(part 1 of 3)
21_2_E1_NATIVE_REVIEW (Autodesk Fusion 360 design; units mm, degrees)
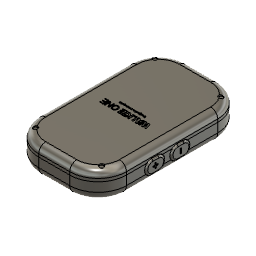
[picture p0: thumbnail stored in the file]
description: Open CASCADE Model
part number: ASSEMBLY
description: Part Number
part number: SOLID
part number: vol_minus_pad_silicone
part number: pcb_clamp_pad_silicone_1_0to0_8_3
part number: play_action_cap_cream
part number: status_lens_clear_diffusing
base_feature "Base Feature1"
base_feature "Base Feature1"
base_feature "Base Feature1"
base_feature "Base Feature1"
base_feature "Base Feature1"
base_feature "Base Feature1"
base_feature "Base Feature1"
base_feature "Base Feature1"
base_feature "Base Feature1"
base_feature "Base Feature1"
base_feature "Base Feature1"
base_feature "Base Feature1"
base_feature "Base Feature1"
base_feature "Base Feature1"
base_feature "Base Feature1"
base_feature "Base Feature1"
base_feature "Base Feature1"
base_feature "Base Feature1"
base_feature "Base Feature1"
base_feature "Base Feature1"
base_feature "Base Feature1"
base_feature "Base Feature1"
base_feature "Base Feature1"
base_feature "Base Feature1"
base_feature "Base Feature1"
base_feature "Base Feature1"
base_feature "Base Feature1"
base_feature "Base Feature1"
base_feature "Base Feature1"
base_feature "Base Feature1"
base_feature "Base Feature1"
base_feature "Base Feature1"
base_feature "Base Feature1"
base_feature "Base Feature1"
base_feature "Base Feature1"
base_feature "Base Feature1"
base_feature "Base Feature1"
base_feature "Base Feature1"
base_feature "Base Feature1"
base_feature "Base Feature1"
base_feature "Base Feature1"
base_feature "Base Feature1"
base_feature "Base Feature1"
base_feature "Base Feature1"
base_feature "Base Feature1"
base_feature "Base Feature1"
base_feature "Base Feature1"
base_feature "Base Feature1"
base_feature "Base Feature1"
base_feature "Base Feature1"
base_feature "Base Feature1"
base_feature "Base Feature1"
base_feature "Base Feature1"
base_feature "Base Feature1"
base_feature "Base Feature1"
base_feature "Base Feature1"
base_feature "Base Feature1"
base_feature "Base Feature1"
base_feature "Base Feature1"
base_feature "Base Feature1"
base_feature "Base Feature1"
base_feature "Base Feature1"
base_feature "Base Feature1"
base_feature "Base Feature1"
base_feature "Base Feature1"
base_feature "Base Feature1"
base_feature "Base Feature1"
base_feature "Base Feature1"
base_feature "Base Feature1"
base_feature "Base Feature1"
base_feature "Base Feature1"
base_feature "Base Feature1"
base_feature "Base Feature1"
base_feature "Base Feature1"
base_feature "Base Feature1"
base_feature "Base Feature1"
base_feature "Base Feature1"
base_feature "Base Feature1"
base_feature "Base Feature1"
base_feature "Base Feature1"
base_feature "Base Feature1"
base_feature "Base Feature1"
base_feature "Base Feature1"
base_feature "Base Feature1"
base_feature "Base Feature1"
base_feature "Base Feature1"
base_feature "Base Feature1"
base_feature "Base Feature1"
base_feature "Base Feature1"
base_feature "Base Feature1"
base_feature "Base Feature1"
base_feature "Base Feature1"
base_feature "Base Feature1"
base_feature "Base Feature1"
base_feature "Base Feature1"
base_feature "Base Feature1"
base_feature "Base Feature1"
base_feature "Base Feature1"
base_feature "Base Feature1"
base_feature "Base Feature1"
base_feature "Base Feature1"
base_feature "Base Feature1"
base_feature "Base Feature1"
base_feature "Base Feature1"
base_feature "Base Feature1"
base_feature "Base Feature1"
base_feature "Base Feature1"
base_feature "Base Feature1"
base_feature "Base Feature1"
base_feature "Base Feature1"
base_feature "Base Feature1"
base_feature "Base Feature1"
base_feature "Base Feature1"
base_feature "Base Feature1"
base_feature "Base Feature1"
base_feature "Base Feature1"
base_feature "Base Feature1"
base_feature "Base Feature1"
base_feature "Base Feature1"
base_feature "Base Feature1"
base_feature "Base Feature1"
base_feature "Base Feature1"
base_feature "Base Feature1"
base_feature "Base Feature1"
base_feature "Base Feature1"
base_feature "Base Feature1"
base_feature "Base Feature1"
base_feature "Base Feature1"
base_feature "Base Feature1"
base_feature "Base Feature1"
base_feature "Base Feature1"
base_feature "Base Feature1"
base_feature "Base Feature1"
base_feature "Base Feature1"
base_feature "Base Feature1"
base_feature "Base Feature1"
base_feature "Base Feature1"
base_feature "Base Feature1"
base_feature "Base Feature1"
base_feature "Base Feature1"
base_feature "Base Feature1"
base_feature "Base Feature1"
base_feature "Base Feature1"
base_feature "Base Feature1"
base_feature "Base Feature1"
base_feature "Base Feature1"
base_feature "Base Feature1"
base_feature "Base Feature1"
base_feature "Base Feature1"
base_feature "Base Feature1"
base_feature "Base Feature1"
base_feature "Base Feature1"
base_feature "Base Feature1"
base_feature "Base Feature1"
base_feature "Base Feature1"
base_feature "Base Feature1"
base_feature "Base Feature1"
base_feature "Base Feature1"
base_feature "Base Feature1"
base_feature "Base Feature1"
base_feature "Base Feature1"
base_feature "Base Feature1"
base_feature "Base Feature1"
base_feature "Base Feature1"
base_feature "Base Feature1"
base_feature "Base Feature1"
base_feature "Base Feature1"
base_feature "Base Feature1"
base_feature "Base Feature1"
base_feature "Base Feature1"
base_feature "Base Feature1"
base_feature "Base Feature1"
base_feature "Base Feature1"
base_feature "Base Feature1"
base_feature "Base Feature1"
base_feature "Base Feature1"
base_feature "Base Feature1"
base_feature "Base Feature1"
base_feature "Base Feature1"
base_feature "Base Feature1"
base_feature "Base Feature1"
base_feature "Base Feature1"
base_feature "Base Feature1"
base_feature "Base Feature1"
base_feature "Base Feature1"
base_feature "Base Feature1"
base_feature "Base Feature1"
base_feature "Base Feature1"
base_feature "Base Feature1"
base_feature "Base Feature1"
base_feature "Base Feature1"
base_feature "Base Feature1"
base_feature "Base Feature1"
base_feature "Base Feature1"
base_feature "Base Feature1"
base_feature "Base Feature1"
base_feature "Base Feature1"
base_feature "Base Feature1"
base_feature "Base Feature1"
base_feature "Base Feature1"
base_feature "Base Feature1"
base_feature "Base Feature1"
base_feature "Base Feature1"
base_feature "Base Feature1"
base_feature "Base Feature1"
base_feature "Base Feature1"
base_feature "Base Feature1"
base_feature "Base Feature1"
base_feature "Base Feature1"
base_feature "Base Feature1"
base_feature "Base Feature1"
base_feature "Base Feature1"
base_feature "Base Feature1"
base_feature "Base Feature1"
base_feature "Base Feature1"
base_feature "Base Feature1"
base_feature "Base Feature1"
base_feature "Base Feature1"
base_feature "Base Feature1"
base_feature "Base Feature1"
base_feature "Base Feature1"
base_feature "Base Feature1"
base_feature "Base Feature1"
base_feature "Base Feature1"
base_feature "Base Feature1"
base_feature "Base Feature1"
base_feature "Base Feature1"
base_feature "Base Feature1"
base_feature "Base Feature1"
base_feature "Base Feature1"
base_feature "Base Feature1"
base_feature "Base Feature1"
base_feature "Base Feature1"
base_feature "Base Feature1"
base_feature "Base Feature1"
base_feature "Base Feature1"
base_feature "Base Feature1"
base_feature "Base Feature1"
base_feature "Base Feature1"
base_feature "Base Feature1"
base_feature "Base Feature1"
base_feature "Base Feature1"
base_feature "Base Feature1"
base_feature "Base Feature1"
base_feature "Base Feature1"
base_feature "Base Feature1"
base_feature "Base Feature1"
base_feature "Base Feature1"
base_feature "Base Feature1"
base_feature "Base Feature1"
base_feature "Base Feature1"
base_feature "Base Feature1"
base_feature "Base Feature1"
base_feature "Base Feature1"
base_feature "Base Feature1"
base_feature "Base Feature1"
base_feature "Base Feature1"
base_feature "Base Feature1"
base_feature "Base Feature1"
base_feature "Base Feature1"
base_feature "Base Feature1"
base_feature "Base Feature1"
base_feature "Base Feature1"
base_feature "Base Feature1"
base_feature "Base Feature1"
base_feature "Base Feature1"
base_feature "Base Feature1"
base_feature "Base Feature1"
base_feature "Base Feature1"
base_feature "Base Feature1"
base_feature "Base Feature1"
base_feature "Base Feature1"
base_feature "Base Feature1"
base_feature "Base Feature1"
base_feature "Base Feature1"
base_feature "Base Feature1"
base_feature "Base Feature1"
base_feature "Base Feature1"
base_feature "Base Feature1"
base_feature "Base Feature1"
base_feature "Base Feature1"
base_feature "Base Feature1"
base_feature "Base Feature1"
base_feature "Base Feature1"
base_feature "Base Feature1"
base_feature "Base Feature1"
base_feature "Base Feature1"
base_feature "Base Feature1"
base_feature "Base Feature1"
base_feature "Base Feature1"
base_feature "Base Feature1"
base_feature "Base Feature1"
base_feature "Base Feature1"
base_feature "Base Feature1"
base_feature "Base Feature1"
base_feature "Base Feature1"
base_feature "Base Feature1"
base_feature "Base Feature1"
base_feature "Base Feature1"
base_feature "Base Feature1"
base_feature "Base Feature1"
base_feature "Base Feature1"
base_feature "Base Feature1"
base_feature "Base Feature1"
base_feature "Base Feature1"
base_feature "Base Feature1"
base_feature "Base Feature1"
base_feature "Base Feature1"
base_feature "Base Feature1"
base_feature "Base Feature1"
base_feature "Base Feature1"
base_feature "Base Feature1"
base_feature "Base Feature1"
base_feature "Base Feature1"
base_feature "Base Feature1"
base_feature "Base Feature1"
base_feature "Base Feature1"
base_feature "Base Feature1"
base_feature "Base Feature1"
base_feature "Base Feature1"
base_feature "Base Feature1"
base_feature "Base Feature1"
base_feature "Base Feature1"
base_feature "Base Feature1"
base_feature "Base Feature1"
base_feature "Base Feature1"
base_feature "Base Feature1"
base_feature "Base Feature1"
base_feature "Base Feature1"
base_feature "Base Feature1"
base_feature "Base Feature1"
base_feature "Base Feature1"
base_feature "Base Feature1"
base_feature "Base Feature1"
base_feature "Base Feature1"
base_feature "Base Feature1"
base_feature "Base Feature1"
base_feature "Base Feature1"
base_feature "Base Feature1"
base_feature "Base Feature1"
base_feature "Base Feature1"
base_feature "Base Feature1"
base_feature "Base Feature1"
base_feature "Base Feature1"
base_feature "Base Feature1"
base_feature "Base Feature1"
base_feature "Base Feature1"
base_feature "Base Feature1"
base_feature "Base Feature1"
base_feature "Base Feature1"
base_feature "Base Feature1"
base_feature "Base Feature1"
base_feature "Base Feature1"
base_feature "Base Feature1"
base_feature "Base Feature1"
base_feature "Base Feature1"
base_feature "Base Feature1"
base_feature "Base Feature1"
base_feature "Base Feature1"
base_feature "Base Feature1"
base_feature "Base Feature1"
base_feature "Base Feature1"
base_feature "Base Feature1"
base_feature "Base Feature1"
base_feature "Base Feature1"
base_feature "Base Feature1"
base_feature "Base Feature1"
base_feature "Base Feature1"
base_feature "Base Feature1"
base_feature "Base Feature1"
base_feature "Base Feature1"
base_feature "Base Feature1"
base_feature "Base Feature1"
base_feature "Base Feature1"
base_feature "Base Feature1"
base_feature "Base Feature1"
base_feature "Base Feature1"
base_feature "Base Feature1"
base_feature "Base Feature1"
base_feature "Base Feature1"
base_feature "Base Feature1"
base_feature "Base Feature1"
base_feature "Base Feature1"
base_feature "Base Feature1"
base_feature "Base Feature1"
base_feature "Base Feature1"
base_feature "Base Feature1"
base_feature "Base Feature1"
base_feature "Base Feature1"
base_feature "Base Feature1"
base_feature "Base Feature1"
base_feature "Base Feature1"
base_feature "Base Feature1"
base_feature "Base Feature1"
base_feature "Base Feature1"
base_feature "Base Feature1"
base_feature "Base Feature1"
base_feature "Base Feature1"
base_feature "Base Feature1"
base_feature "Base Feature1"
base_feature "Base Feature1"
base_feature "Base Feature1"
base_feature "Base Feature1"
base_feature "Base Feature1"
base_feature "Base Feature1"
base_feature "Base Feature1"
base_feature "Base Feature1"
base_feature "Base Feature1"
base_feature "Base Feature1"
base_feature "Base Feature1"
base_feature "Base Feature1"
base_feature "Base Feature1"
base_feature "Base Feature1"
base_feature "Base Feature1"
base_feature "Base Feature1"
base_feature "Base Feature1"
base_feature "Base Feature1"
base_feature "Base Feature1"
base_feature "Base Feature1"
base_feature "Base Feature1"
base_feature "Base Feature1"
base_feature "Base Feature1"
base_feature "Base Feature1"
base_feature "Base Feature1"
base_feature "Base Feature1"
base_feature "Base Feature1"
base_feature "Base Feature1"
base_feature "Base Feature1"
base_feature "Base Feature1"
base_feature "Base Feature1"
base_feature "Base Feature1"
base_feature "Base Feature1"
base_feature "Base Feature1"
base_feature "Base Feature1"
base_feature "Base Feature1"
base_feature "Base Feature1"
base_feature "Base Feature1"
base_feature "Base Feature1"
base_feature "Base Feature1"
base_feature "Base Feature1"
base_feature "Base Feature1"
base_feature "Base Feature1"
base_feature "Base Feature1"
base_feature "Base Feature1"
base_feature "Base Feature1"
base_feature "Base Feature1"
base_feature "Base Feature1"
base_feature "Base Feature1"
base_feature "Base Feature1"
base_feature "Base Feature1"
base_feature "Base Feature1"
base_feature "Base Feature1"
base_feature "Base Feature1"
base_feature "Base Feature1"
base_feature "Base Feature1"
base_feature "Base Feature1"
base_feature "Base Feature1"
base_feature "Base Feature1"
base_feature "Base Feature1"
base_feature "Base Feature1"
base_feature "Base Feature1"
base_feature "Base Feature1"
base_feature "Base Feature1"
base_feature "Base Feature1"
base_feature "Base Feature1"
base_feature "Base Feature1"
base_feature "Base Feature1"
base_feature "Base Feature1"
base_feature "Base Feature1"
base_feature "Base Feature1"
base_feature "Base Feature1"
base_feature "Base Feature1"
base_feature "Base Feature1"
base_feature "Base Feature1"
base_feature "Base Feature1"
base_feature "Base Feature1"
base_feature "Base Feature1"
base_feature "Base Feature1"
base_feature "Base Feature1"
base_feature "Base Feature1"
base_feature "Base Feature1"
base_feature "Base Feature1"
base_feature "Base Feature1"
base_feature "Base Feature1"
base_feature "Base Feature1"
base_feature "Base Feature1"
base_feature "Base Feature1"
base_feature "Base Feature1"
base_feature "Base Feature1"
base_feature "Base Feature1"
base_feature "Base Feature1"
base_feature "Base Feature1"
base_feature "Base Feature1"
base_feature "Base Feature1"
base_feature "Base Feature1"
base_feature "Base Feature1"
base_feature "Base Feature1"
base_feature "Base Feature1"
base_feature "Base Feature1"
base_feature "Base Feature1"
base_feature "Base Feature1"
base_feature "Base Feature1"
base_feature "Base Feature1"
base_feature "Base Feature1"
base_feature "Base Feature1"
base_feature "Base Feature1"
base_feature "Base Feature1"
base_feature "Base Feature1"
base_feature "Base Feature1"
base_feature "Base Feature1"
base_feature "Base Feature1"
base_feature "Base Feature1"
base_feature "Base Feature1"
base_feature "Base Feature1"
base_feature "Base Feature1"
base_feature "Base Feature1"
base_feature "Base Feature1"
base_feature "Base Feature1"
base_feature "Base Feature1"
base_feature "Base Feature1"
base_feature "Base Feature1"
base_feature "Base Feature1"
base_feature "Base Feature1"
base_feature "Base Feature1"
base_feature "Base Feature1"
base_feature "Base Feature1"
base_feature "Base Feature1"
base_feature "Base Feature1"
base_feature "Base Feature1"
base_feature "Base Feature1"
base_feature "Base Feature1"
base_feature "Base Feature1"
base_feature "Base Feature1"
base_feature "Base Feature1"
base_feature "Base Feature1"
base_feature "Base Feature1"
base_feature "Base Feature1"
base_feature "Base Feature1"
base_feature "Base Feature1"
base_feature "Base Feature1"
base_feature "Base Feature1"
base_feature "Base Feature1"
base_feature "Base Feature1"
base_feature "Base Feature1"
base_feature "Base Feature1"
base_feature "Base Feature1"
base_feature "Base Feature1"
base_feature "Base Feature1"
base_feature "Base Feature1"
base_feature "Base Feature1"
base_feature "Base Feature1"
base_feature "Base Feature1"
base_feature "Base Feature1"
base_feature "Base Feature1"
base_feature "Base Feature1"
base_feature "Base Feature1"
base_feature "Base Feature1"
base_feature "Base Feature1"
base_feature "Base Feature1"
base_feature "Base Feature1"
base_feature "Base Feature1"
base_feature "Base Feature1"
base_feature "Base Feature1"
base_feature "Base Feature1"
base_feature "Base Feature1"
base_feature "Base Feature1"
base_feature "Base Feature1"
base_feature "Base Feature1"
base_feature "Base Feature1"
base_feature "Base Feature1"
base_feature "Base Feature1"
base_feature "Base Feature1"
base_feature "Base Feature1"
base_feature "Base Feature1"
base_feature "Base Feature1"
base_feature "Base Feature1"
base_feature "Base Feature1"
base_feature "Base Feature1"
base_feature "Base Feature1"
base_feature "Base Feature1"
base_feature "Base Feature1"
base_feature "Base Feature1"
base_feature "Base Feature1"
base_feature "Base Feature1"
base_feature "Base Feature1"
base_feature "Base Feature1"
base_feature "Base Feature1"
base_feature "Base Feature1"
base_feature "Base Feature1"
base_feature "Base Feature1"
base_feature "Base Feature1"
base_feature "Base Feature1"
base_feature "Base Feature1"
base_feature "Base Feature1"
base_feature "Base Feature1"
base_feature "Base Feature1"
base_feature "Base Feature1"
base_feature "Base Feature1"
base_feature "Base Feature1"
base_feature "Base Feature1"
base_feature "Base Feature1"
base_feature "Base Feature1"
base_feature "Base Feature1"
base_feature "Base Feature1"
base_feature "Base Feature1"
base_feature "Base Feature1"
base_feature "Base Feature1"
base_feature "Base Feature1"
base_feature "Base Feature1"
base_feature "Base Feature1"
base_feature "Base Feature1"
base_feature "Base Feature1"
base_feature "Base Feature1"
base_feature "Base Feature1"
base_feature "Base Feature1"
base_feature "Base Feature1"
base_feature "Base Feature1"
base_feature "Base Feature1"
base_feature "Base Feature1"
base_feature "Base Feature1"
base_feature "Base Feature1"
base_feature "Base Feature1"
base_feature "Base Feature1"
base_feature "Base Feature1"
base_feature "Base Feature1"
base_feature "Base Feature1"
base_feature "Base Feature1"
base_feature "Base Feature1"
base_feature "Base Feature1"
base_feature "Base Feature1"
base_feature "Base Feature1"
base_feature "Base Feature1"
base_feature "Base Feature1"
base_feature "Base Feature1"
base_feature "Base Feature1"
base_feature "Base Feature1"
base_feature "Base Feature1"
base_feature "Base Feature1"
base_feature "Base Feature1"
base_feature "Base Feature1"
base_feature "Base Feature1"
base_feature "Base Feature1"
base_feature "Base Feature1"
base_feature "Base Feature1"
base_feature "Base Feature1"
base_feature "Base Feature1"
base_feature "Base Feature1"
base_feature "Base Feature1"
base_feature "Base Feature1"
base_feature "Base Feature1"
base_feature "Base Feature1"
base_feature "Base Feature1"
base_feature "Base Feature1"
base_feature "Base Feature1"
base_feature "Base Feature1"
base_feature "Base Feature1"
base_feature "Base Feature1"
base_feature "Base Feature1"
base_feature "Base Feature1"
base_feature "Base Feature1"
base_feature "Base Feature1"
base_feature "Base Feature1"
base_feature "Base Feature1"
base_feature "Base Feature1"
base_feature "Base Feature1"
base_feature "Base Feature1"
base_feature "Base Feature1"
base_feature "Base Feature1"
base_feature "Base Feature1"
base_feature "Base Feature1"
base_feature "Base Feature1"
base_feature "Base Feature1"
base_feature "Base Feature1"
base_feature "Base Feature1"
base_feature "Base Feature1"
base_feature "Base Feature1"
base_feature "Base Feature1"
base_feature "Base Feature1"
base_feature "Base Feature1"
base_feature "Base Feature1"
base_feature "Base Feature1"
base_feature "Base Feature1"
base_feature "Base Feature1"
base_feature "Base Feature1"
base_feature "Base Feature1"
base_feature "Base Feature1"
base_feature "Base Feature1"
base_feature "Base Feature1"
base_feature "Base Feature1"
base_feature "Base Feature1"
base_feature "Base Feature1"
base_feature "Base Feature1"
base_feature "Base Feature1"
base_feature "Base Feature1"
base_feature "Base Feature1"
base_feature "Base Feature1"
base_feature "Base Feature1"
base_feature "Base Feature1"
base_feature "Base Feature1"
base_feature "Base Feature1"
base_feature "Base Feature1"
base_feature "Base Feature1"
base_feature "Base Feature1"
base_feature "Base Feature1"
base_feature "Base Feature1"
base_feature "Base Feature1"
base_feature "Base Feature1"
base_feature "Base Feature1"
base_feature "Base Feature1"
base_feature "Base Feature1"
base_feature "Base Feature1"
base_feature "Base Feature1"
base_feature "Base Feature1"
base_feature "Base Feature1"
base_feature "Base Feature1"
base_feature "Base Feature1"
base_feature "Base Feature1"
base_feature "Base Feature1"
base_feature "Base Feature1"
base_feature "Base Feature1"
base_feature "Base Feature1"
base_feature "Base Feature1"
base_feature "Base Feature1"
base_feature "Base Feature1"
base_feature "Base Feature1"
base_feature "Base Feature1"
base_feature "Base Feature1"
base_feature "Base Feature1"
base_feature "Base Feature1"
base_feature "Base Feature1"
base_feature "Base Feature1"
base_feature "Base Feature1"
base_feature "Base Feature1"
base_feature "Base Feature1"
base_feature "Base Feature1"
base_feature "Base Feature1"
base_feature "Base Feature1"
base_feature "Base Feature1"
base_feature "Base Feature1"
base_feature "Base Feature1"
base_feature "Base Feature1"
base_feature "Base Feature1"
base_feature "Base Feature1"
base_feature "Base Feature1"
base_feature "Base Feature1"
base_feature "Base Feature1"
base_feature "Base Feature1"
base_feature "Base Feature1"
base_feature "Base Feature1"
base_feature "Base Feature1"
base_feature "Base Feature1"
base_feature "Base Feature1"
base_feature "Base Feature1"
base_feature "Base Feature1"
base_feature "Base Feature1"
base_feature "Base Feature1"
base_feature "Base Feature1"
base_feature "Base Feature1"
base_feature "Base Feature1"
base_feature "Base Feature1"
base_feature "Base Feature1"
base_feature "Base Feature1"
base_feature "Base Feature1"
base_feature "Base Feature1"
base_feature "Base Feature1"
base_feature "Base Feature1"
base_feature "Base Feature1"
base_feature "Base Feature1"
base_feature "Base Feature1"
base_feature "Base Feature1"
base_feature "Base Feature1"
base_feature "Base Feature1"
base_feature "Base Feature1"
base_feature "Base Feature1"
base_feature "Base Feature1"
base_feature "Base Feature1"
base_feature "Base Feature1"
base_feature "Base Feature1"
base_feature "Base Feature1"
base_feature "Base Feature1"
base_feature "Base Feature1"
base_feature "Base Feature1"
base_feature "Base Feature1"
base_feature "Base Feature1"
base_feature "Base Feature1"
base_feature "Base Feature1"
base_feature "Base Feature1"
base_feature "Base Feature1"
base_feature "Base Feature1"
base_feature "Base Feature1"
base_feature "Base Feature1"
base_feature "Base Feature1"
base_feature "Base Feature1"
base_feature "Base Feature1"
base_feature "Base Feature1"
base_feature "Base Feature1"
base_feature "Base Feature1"
base_feature "Base Feature1"
base_feature "Base Feature1"
base_feature "Base Feature1"
base_feature "Base Feature1"
base_feature "Base Feature1"
base_feature "Base Feature1"
base_feature "Base Feature1"
base_feature "Base Feature1"
base_feature "Base Feature1"
base_feature "Base Feature1"
base_feature "Base Feature1"
base_feature "Base Feature1"
base_feature "Base Feature1"
base_feature "Base Feature1"
base_feature "Base Feature1"
base_feature "Base Feature1"
base_feature "Base Feature1"
base_feature "Base Feature1"
base_feature "Base Feature1"
base_feature "Base Feature1"
base_feature "Base Feature1"
base_feature "Base Feature1"
base_feature "Base Feature1"
base_feature "Base Feature1"
base_feature "Base Feature1"
base_feature "Base Feature1"
base_feature "Base Feature1"
base_feature "Base Feature1"
base_feature "Base Feature1"
base_feature "Base Feature1"
base_feature "Base Feature1"
base_feature "Base Feature1"
base_feature "Base Feature1"
base_feature "Base Feature1"
base_feature "Base Feature1"
base_feature "Base Feature1"
base_feature "Base Feature1"
base_feature "Base Feature1"
base_feature "Base Feature1"
base_feature "Base Feature1"
base_feature "Base Feature1"
base_feature "Base Feature1"
base_feature "Base Feature1"
base_feature "Base Feature1"
base_feature "Base Feature1"
base_feature "Base Feature1"
base_feature "Base Feature1"
base_feature "Base Feature1"
base_feature "Base Feature1"
base_feature "Base Feature1"
base_feature "Base Feature1"
base_feature "Base Feature1"
base_feature "Base Feature1"
base_feature "Base Feature1"
base_feature "Base Feature1"
base_feature "Base Feature1"
base_feature "Base Feature1"
base_feature "Base Feature1"
base_feature "Base Feature1"
base_feature "Base Feature1"
base_feature "Base Feature1"
base_feature "Base Feature1"
base_feature "Base Feature1"
base_feature "Base Feature1"
base_feature "Base Feature1"
base_feature "Base Feature1"
base_feature "Base Feature1"
base_feature "Base Feature1"
base_feature "Base Feature1"
base_feature "Base Feature1"
base_feature "Base Feature1"
base_feature "Base Feature1"
base_feature "Base Feature1"
base_feature "Base Feature1"
base_feature "Base Feature1"
base_feature "Base Feature1"
base_feature "Base Feature1"
base_feature "Base Feature1"
base_feature "Base Feature1"
base_feature "Base Feature1"
base_feature "Base Feature1"
base_feature "Base Feature1"
base_feature "Base Feature1"
base_feature "Base Feature1"
base_feature "Base Feature1"
base_feature "Base Feature1"
base_feature "Base Feature1"
base_feature "Base Feature1"
base_feature "Base Feature1"
base_feature "Base Feature1"
base_feature "Base Feature1"
base_feature "Base Feature1"
base_feature "Base Feature1"
base_feature "Base Feature1"
base_feature "Base Feature1"
base_feature "Base Feature1"
base_feature "Base Feature1"
base_feature "Base Feature1"
base_feature "Base Feature1"
base_feature "Base Feature1"
base_feature "Base Feature1"
base_feature "Base Feature1"
base_feature "Base Feature1"
base_feature "Base Feature1"
base_feature "Base Feature1"
base_feature "Base Feature1"
base_feature "Base Feature1"
base_feature "Base Feature1"
base_feature "Base Feature1"
base_feature "Base Feature1"
base_feature "Base Feature1"
base_feature "Base Feature1"
base_feature "Base Feature1"
base_feature "Base Feature1"
base_feature "Base Feature1"
base_feature "Base Feature1"
base_feature "Base Feature1"
base_feature "Base Feature1"
base_feature "Base Feature1"
base_feature "Base Feature1"
base_feature "Base Feature1"
base_feature "Base Feature1"
base_feature "Base Feature1"
base_feature "Base Feature1"
base_feature "Base Feature1"
base_feature "Base Feature1"
base_feature "Base Feature1"
base_feature "Base Feature1"
base_feature "Base Feature1"
base_feature "Base Feature1"
base_feature "Base Feature1"
base_feature "Base Feature1"
base_feature "Base Feature1"
base_feature "Base Feature1"
base_feature "Base Feature1"
base_feature "Base Feature1"
base_feature "Base Feature1"
base_feature "Base Feature1"
base_feature "Base Feature1"
base_feature "Base Feature1"
base_feature "Base Feature1"
base_feature "Base Feature1"
base_feature "Base Feature1"
base_feature "Base Feature1"
base_feature "Base Feature1"
base_feature "Base Feature1"
base_feature "Base Feature1"
base_feature "Base Feature1"
base_feature "Base Feature1"
base_feature "Base Feature1"
base_feature "Base Feature1"
base_feature "Base Feature1"
base_feature "Base Feature1"
base_feature "Base Feature1"
base_feature "Base Feature1"
base_feature "Base Feature1"
base_feature "Base Feature1"
base_feature "Base Feature1"
base_feature "Base Feature1"
base_feature "Base Feature1"
base_feature "Base Feature1"
base_feature "Base Feature1"
base_feature "Base Feature1"
base_feature "Base Feature1"
base_feature "Base Feature1"
base_feature "Base Feature1"
base_feature "Base Feature1"
base_feature "Base Feature1"
base_feature "Base Feature1"
base_feature "Base Feature1"
base_feature "Base Feature1"
base_feature "Base Feature1"
base_feature "Base Feature1"
base_feature "Base Feature1"
base_feature "Base Feature1"
base_feature "Base Feature1"
base_feature "Base Feature1"
base_feature "Base Feature1"
base_feature "Base Feature1"
base_feature "Base Feature1"
base_feature "Base Feature1"
base_feature "Base Feature1"
base_feature "Base Feature1"
base_feature "Base Feature1"
base_feature "Base Feature1"
base_feature "Base Feature1"
base_feature "Base Feature1"
base_feature "Base Feature1"
base_feature "Base Feature1"
base_feature "Base Feature1"
base_feature "Base Feature1"
base_feature "Base Feature1"
base_feature "Base Feature1"
base_feature "Base Feature1"
base_feature "Base Feature1"
base_feature "Base Feature1"
base_feature "Base Feature1"
base_feature "Base Feature1"
base_feature "Base Feature1"
base_feature "Base Feature1"
base_feature "Base Feature1"
base_feature "Base Feature1"
base_feature "Base Feature1"
base_feature "Base Feature1"
base_feature "Base Feature1"
base_feature "Base Feature1"
base_feature "Base Feature1"
base_feature "Base Feature1"
base_feature "Base Feature1"
base_feature "Base Feature1"
base_feature "Base Feature1"
base_feature "Base Feature1"
base_feature "Base Feature1"
base_feature "Base Feature1"
base_feature "Base Feature1"
base_feature "Base Feature1"
base_feature "Base Feature1"
base_feature "Base Feature1"
base_feature "Base Feature1"
base_feature "Base Feature1"
base_feature "Base Feature1"
base_feature "Base Feature1"
base_feature "Base Feature1"
base_feature "Base Feature1"
base_feature "Base Feature1"
base_feature "Base Feature1"
base_feature "Base Feature1"
base_feature "Base Feature1"
base_feature "Base Feature1"
base_feature "Base Feature1"
base_feature "Base Feature1"
base_feature "Base Feature1"
base_feature "Base Feature1"
base_feature "Base Feature1"
base_feature "Base Feature1"
base_feature "Base Feature1"
base_feature "Base Feature1"
base_feature "Base Feature1"
base_feature "Base Feature1"
base_feature "Base Feature1"
base_feature "Base Feature1"
base_feature "Base Feature1"
base_feature "Base Feature1"
base_feature "Base Feature1"
base_feature "Base Feature1"
base_feature "Base Feature1"
base_feature "Base Feature1"
base_feature "Base Feature1"
base_feature "Base Feature1"
base_feature "Base Feature1"
base_feature "Base Feature1"
base_feature "Base Feature1"
base_feature "Base Feature1"
base_feature "Base Feature1"
base_feature "Base Feature1"
base_feature "Base Feature1"
base_feature "Base Feature1"
base_feature "Base Feature1"
base_feature "Base Feature1"
base_feature "Base Feature1"
base_feature "Base Feature1"
base_feature "Base Feature1"
base_feature "Base Feature1"
base_feature "Base Feature1"
base_feature "Base Feature1"
base_feature "Base Feature1"
base_feature "Base Feature1"
base_feature "Base Feature1"
base_feature "Base Feature1"
base_feature "Base Feature1"
base_feature "Base Feature1"
base_feature "Base Feature1"
base_feature "Base Feature1"
base_feature "Base Feature1"
base_feature "Base Feature1"
base_feature "Base Feature1"
base_feature "Base Feature1"
base_feature "Base Feature1"
base_feature "Base Feature1"
base_feature "Base Feature1"
base_feature "Base Feature1"
base_feature "Base Feature1"
base_feature "Base Feature1"
base_feature "Base Feature1"
base_feature "Base Feature1"
base_feature "Base Feature1"
base_feature "Base Feature1"
base_feature "Base Feature1"
base_feature "Base Feature1"
base_feature "Base Feature1"
base_feature "Base Feature1"
base_feature "Base Feature1"
base_feature "Base Feature1"
base_feature "Base Feature1"
base_feature "Base Feature1"
base_feature "Base Feature1"
base_feature "Base Feature1"
base_feature "Base Feature1"
base_feature "Base Feature1"
base_feature "Base Feature1"
base_feature "Base Feature1"
base_feature "Base Feature1"
base_feature "Base Feature1"
base_feature "Base Feature1"
base_feature "Base Feature1"
base_feature "Base Feature1"
base_feature "Base Feature1"
base_feature "Base Feature1"
base_feature "Base Feature1"
base_feature "Base Feature1"
base_feature "Base Feature1"
base_feature "Base Feature1"
base_feature "Base Feature1"
base_feature "Base Feature1"
base_feature "Base Feature1"
base_feature "Base Feature1"
base_feature "Base Feature1"
base_feature "Base Feature1"
base_feature "Base Feature1"
base_feature "Base Feature1"
base_feature "Base Feature1"
base_feature "Base Feature1"
base_feature "Base Feature1"
base_feature "Base Feature1"
base_feature "Base Feature1"
base_feature "Base Feature1"
base_feature "Base Feature1"
base_feature "Base Feature1"
base_feature "Base Feature1"
base_feature "Base Feature1"
base_feature "Base Feature1"
base_feature "Base Feature1"
base_feature "Base Feature1"
base_feature "Base Feature1"
base_feature "Base Feature1"
base_feature "Base Feature1"
base_feature "Base Feature1"
base_feature "Base Feature1"
base_feature "Base Feature1"
base_feature "Base Feature1"
base_feature "Base Feature1"
base_feature "Base Feature1"
base_feature "Base Feature1"
base_feature "Base Feature1"
base_feature "Base Feature1"
base_feature "Base Feature1"
base_feature "Base Feature1"
base_feature "Base Feature1"
base_feature "Base Feature1"
base_feature "Base Feature1"
base_feature "Base Feature1"
base_feature "Base Feature1"
base_feature "Base Feature1"
base_feature "Base Feature1"
base_feature "Base Feature1"
base_feature "Base Feature1"
base_feature "Base Feature1"
base_feature "Base Feature1"
base_feature "Base Feature1"
base_feature "Base Feature1"
base_feature "Base Feature1"
base_feature "Base Feature1"
base_feature "Base Feature1"
base_feature "Base Feature1"
base_feature "Base Feature1"
base_feature "Base Feature1"
base_feature "Base Feature1"
base_feature "Base Feature1"
base_feature "Base Feature1"
base_feature "Base Feature1"
base_feature "Base Feature1"
base_feature "Base Feature1"
base_feature "Base Feature1"
base_feature "Base Feature1"
base_feature "Base Feature1"
base_feature "Base Feature1"
base_feature "Base Feature1"
base_feature "Base Feature1"
base_feature "Base Feature1"
base_feature "Base Feature1"
base_feature "Base Feature1"
base_feature "Base Feature1"
base_feature "Base Feature1"
base_feature "Base Feature1"
base_feature "Base Feature1"
base_feature "Base Feature1"
base_feature "Base Feature1"
base_feature "Base Feature1"
base_feature "Base Feature1"
base_feature "Base Feature1"
base_feature "Base Feature1"
base_feature "Base Feature1"
base_feature "Base Feature1"
base_feature "Base Feature1"
base_feature "Base Feature1"
base_feature "Base Feature1"
base_feature "Base Feature1"
base_feature "Base Feature1"
base_feature "Base Feature1"
base_feature "Base Feature1"
base_feature "Base Feature1"
base_feature "Base Feature1"
base_feature "Base Feature1"
base_feature "Base Feature1"
base_feature "Base Feature1"
base_feature "Base Feature1"
base_feature "Base Feature1"
base_feature "Base Feature1"
base_feature "Base Feature1"
base_feature "Base Feature1"
base_feature "Base Feature1"
base_feature "Base Feature1"
base_feature "Base Feature1"
base_feature "Base Feature1"
base_feature "Base Feature1"
base_feature "Base Feature1"
base_feature "Base Feature1"
base_feature "Base Feature1"
base_feature "Base Feature1"
base_feature "Base Feature1"
base_feature "Base Feature1"
base_feature "Base Feature1"
base_feature "Base Feature1"
base_feature "Base Feature1"
base_feature "Base Feature1"
base_feature "Base Feature1"
base_feature "Base Feature1"
base_feature "Base Feature1"
base_feature "Base Feature1"
base_feature "Base Feature1"
base_feature "Base Feature1"
base_feature "Base Feature1"
base_feature "Base Feature1"
base_feature "Base Feature1"
base_feature "Base Feature1"
base_feature "Base Feature1"
base_feature "Base Feature1"
base_feature "Base Feature1"
base_feature "Base Feature1"
base_feature "Base Feature1"
base_feature "Base Feature1"
base_feature "Base Feature1"
base_feature "Base Feature1"
base_feature "Base Feature1"
base_feature "Base Feature1"
base_feature "Base Feature1"
base_feature "Base Feature1"
base_feature "Base Feature1"
base_feature "Base Feature1"
base_feature "Base Feature1"
base_feature "Base Feature1"
base_feature "Base Feature1"
base_feature "Base Feature1"
base_feature "Base Feature1"
base_feature "Base Feature1"
base_feature "Base Feature1"
base_feature "Base Feature1"
base_feature "Base Feature1"
base_feature "Base Feature1"
base_feature "Base Feature1"
base_feature "Base Feature1"
base_feature "Base Feature1"
base_feature "Base Feature1"
base_feature "Base Feature1"
base_feature "Base Feature1"
base_feature "Base Feature1"
base_feature "Base Feature1"
base_feature "Base Feature1"
base_feature "Base Feature1"
base_feature "Base Feature1"
base_feature "Base Feature1"
base_feature "Base Feature1"
base_feature "Base Feature1"
base_feature "Base Feature1"
base_feature "Base Feature1"
base_feature "Base Feature1"
base_feature "Base Feature1"
base_feature "Base Feature1"
base_feature "Base Feature1"
base_feature "Base Feature1"
base_feature "Base Feature1"
base_feature "Base Feature1"
base_feature "Base Feature1"
base_feature "Base Feature1"
base_feature "Base Feature1"
base_feature "Base Feature1"
base_feature "Base Feature1"
base_feature "Base Feature1"
base_feature "Base Feature1"
base_feature "Base Feature1"
base_feature "Base Feature1"
base_feature "Base Feature1"
base_feature "Base Feature1"
base_feature "Base Feature1"
base_feature "Base Feature1"
base_feature "Base Feature1"
base_feature "Base Feature1"
base_feature "Base Feature1"
base_feature "Base Feature1"
base_feature "Base Feature1"
base_feature "Base Feature1"
base_feature "Base Feature1"
base_feature "Base Feature1"
base_feature "Base Feature1"
base_feature "Base Feature1"
base_feature "Base Feature1"
base_feature "Base Feature1"
base_feature "Base Feature1"
base_feature "Base Feature1"
base_feature "Base Feature1"
base_feature "Base Feature1"
base_feature "Base Feature1"
base_feature "Base Feature1"
base_feature "Base Feature1"
base_feature "Base Feature1"
base_feature "Base Feature1"
base_feature "Base Feature1"
base_feature "Base Feature1"
base_feature "Base Feature1"
base_feature "Base Feature1"
base_feature "Base Feature1"
base_feature "Base Feature1"
base_feature "Base Feature1"
base_feature "Base Feature1"
base_feature "Base Feature1"
base_feature "Base Feature1"
base_feature "Base Feature1"
base_feature "Base Feature1"
base_feature "Base Feature1"
base_feature "Base Feature1"
base_feature "Base Feature1"
base_feature "Base Feature1"
base_feature "Base Feature1"
base_feature "Base Feature1"
base_feature "Base Feature1"
base_feature "Base Feature1"
base_feature "Base Feature1"
base_feature "Base Feature1"
base_feature "Base Feature1"
base_feature "Base Feature1"
base_feature "Base Feature1"
base_feature "Base Feature1"
base_feature "Base Feature1"
base_feature "Base Feature1"
base_feature "Base Feature1"
base_feature "Base Feature1"
base_feature "Base Feature1"
base_feature "Base Feature1"
base_feature "Base Feature1"
base_feature "Base Feature1"
base_feature "Base Feature1"
base_feature "Base Feature1"
base_feature "Base Feature1"
base_feature "Base Feature1"
base_feature "Base Feature1"
base_feature "Base Feature1"
base_feature "Base Feature1"
base_feature "Base Feature1"
base_feature "Base Feature1"
base_feature "Base Feature1"
base_feature "Base Feature1"
base_feature "Base Feature1"
base_feature "Base Feature1"
base_feature "Base Feature1"
base_feature "Base Feature1"
base_feature "Base Feature1"
base_feature "Base Feature1"
base_feature "Base Feature1"
base_feature "Base Feature1"
base_feature "Base Feature1"
base_feature "Base Feature1"
base_feature "Base Feature1"
base_feature "Base Feature1"
base_feature "Base Feature1"
base_feature "Base Feature1"
base_feature "Base Feature1"
base_feature "Base Feature1"
base_feature "Base Feature1"
base_feature "Base Feature1"
base_feature "Base Feature1"
base_feature "Base Feature1"
base_feature "Base Feature1"
base_feature "Base Feature1"
base_feature "Base Feature1"
base_feature "Base Feature1"
base_feature "Base Feature1"
base_feature "Base Feature1"
base_feature "Base Feature1"
base_feature "Base Feature1"
base_feature "Base Feature1"
base_feature "Base Feature1"
base_feature "Base Feature1"
base_feature "Base Feature1"
base_feature "Base Feature1"
base_feature "Base Feature1"
base_feature "Base Feature1"
base_feature "Base Feature1"
base_feature "Base Feature1"
base_feature "Base Feature1"
base_feature "Base Feature1"
base_feature "Base Feature1"
base_feature "Base Feature1"
base_feature "Base Feature1"
base_feature "Base Feature1"
base_feature "Base Feature1"
base_feature "Base Feature1"
base_feature "Base Feature1"
base_feature "Base Feature1"
base_feature "Base Feature1"
base_feature "Base Feature1"
base_feature "Base Feature1"
base_feature "Base Feature1"
base_feature "Base Feature1"
base_feature "Base Feature1"
base_feature "Base Feature1"
base_feature "Base Feature1"
base_feature "Base Feature1"
base_feature "Base Feature1"
base_feature "Base Feature1"
base_feature "Base Feature1"
base_feature "Base Feature1"
base_feature "Base Feature1"
base_feature "Base Feature1"
base_feature "Base Feature1"
base_feature "Base Feature1"
base_feature "Base Feature1"
base_feature "Base Feature1"
base_feature "Base Feature1"
base_feature "Base Feature1"
base_feature "Base Feature1"
base_feature "Base Feature1"
base_feature "Base Feature1"
base_feature "Base Feature1"
base_feature "Base Feature1"
base_feature "Base Feature1"
base_feature "Base Feature1"
base_feature "Base Feature1"
base_feature "Base Feature1"
base_feature "Base Feature1"
base_feature "Base Feature1"
base_feature "Base Feature1"
base_feature "Base Feature1"
base_feature "Base Feature1"
base_feature "Base Feature1"
base_feature "Base Feature1"
base_feature "Base Feature1"
base_feature "Base Feature1"
base_feature "Base Feature1"
base_feature "Base Feature1"
base_feature "Base Feature1"
base_feature "Base Feature1"
base_feature "Base Feature1"
base_feature "Base Feature1"
base_feature "Base Feature1"
base_feature "Base Feature1"
base_feature "Base Feature1"
base_feature "Base Feature1"
base_feature "Base Feature1"
base_feature "Base Feature1"
base_feature "Base Feature1"
base_feature "Base Feature1"
base_feature "Base Feature1"
base_feature "Base Feature1"
base_feature "Base Feature1"
base_feature "Base Feature1"
base_feature "Base Feature1"
base_feature "Base Feature1"
base_feature "Base Feature1"
base_feature "Base Feature1"
base_feature "Base Feature1"
base_feature "Base Feature1"
base_feature "Base Feature1"
base_feature "Base Feature1"
base_feature "Base Feature1"
base_feature "Base Feature1"
base_feature "Base Feature1"
base_feature "Base Feature1"
base_feature "Base Feature1"
base_feature "Base Feature1"
base_feature "Base Feature1"
base_feature "Base Feature1"
base_feature "Base Feature1"
base_feature "Base Feature1"
base_feature "Base Feature1"
base_feature "Base Feature1"
base_feature "Base Feature1"
base_feature "Base Feature1"
base_feature "Base Feature1"
base_feature "Base Feature1"
base_feature "Base Feature1"
base_feature "Base Feature1"
base_feature "Base Feature1"
base_feature "Base Feature1"
base_feature "Base Feature1"
base_feature "Base Feature1"
base_feature "Base Feature1"
base_feature "Base Feature1"
base_feature "Base Feature1"
base_feature "Base Feature1"
base_feature "Base Feature1"
base_feature "Base Feature1"
base_feature "Base Feature1"
base_feature "Base Feature1"
base_feature "Base Feature1"
base_feature "Base Feature1"
base_feature "Base Feature1"
base_feature "Base Feature1"
base_feature "Base Feature1"
base_feature "Base Feature1"
base_feature "Base Feature1"
base_feature "Base Feature1"
base_feature "Base Feature1"
base_feature "Base Feature1"
base_feature "Base Feature1"
base_feature "Base Feature1"
base_feature "Base Feature1"
base_feature "Base Feature1"
base_feature "Base Feature1"
base_feature "Base Feature1"
base_feature "Base Feature1"
base_feature "Base Feature1"
base_feature "Base Feature1"
base_feature "Base Feature1"
base_feature "Base Feature1"
base_feature "Base Feature1"
base_feature "Base Feature1"
base_feature "Base Feature1"
base_feature "Base Feature1"
base_feature "Base Feature1"
base_feature "Base Feature1"
base_feature "Base Feature1"
base_feature "Base Feature1"
base_feature "Base Feature1"
base_feature "Base Feature1"
base_feature "Base Feature1"
base_feature "Base Feature1"
base_feature "Base Feature1"
base_feature "Base Feature1"
base_feature "Base Feature1"
base_feature "Base Feature1"
base_feature "Base Feature1"
base_feature "Base Feature1"
base_feature "Base Feature1"
base_feature "Base Feature1"
base_feature "Base Feature1"
base_feature "Base Feature1"
base_feature "Base Feature1"
base_feature "Base Feature1"
base_feature "Base Feature1"
base_feature "Base Feature1"
base_feature "Base Feature1"
base_feature "Base Feature1"
base_feature "Base Feature1"
base_feature "Base Feature1"
base_feature "Base Feature1"
base_feature "Base Feature1"
base_feature "Base Feature1"
base_feature "Base Feature1"
base_feature "Base Feature1"
base_feature "Base Feature1"
base_feature "Base Feature1"
base_feature "Base Feature1"
base_feature "Base Feature1"
base_feature "Base Feature1"
base_feature "Base Feature1"
base_feature "Base Feature1"
base_feature "Base Feature1"
base_feature "Base Feature1"
base_feature "Base Feature1"
base_feature "Base Feature1"
base_feature "Base Feature1"
base_feature "Base Feature1"
base_feature "Base Feature1"
base_feature "Base Feature1"
base_feature "Base Feature1"
base_feature "Base Feature1"
base_feature "Base Feature1"
base_feature "Base Feature1"
base_feature "Base Feature1"
base_feature "Base Feature1"
base_feature "Base Feature1"
base_feature "Base Feature1"
base_feature "Base Feature1"
base_feature "Base Feature1"
base_feature "Base Feature1"
base_feature "Base Feature1"
base_feature "Base Feature1"
base_feature "Base Feature1"
base_feature "Base Feature1"
base_feature "Base Feature1"
base_feature "Base Feature1"
base_feature "Base Feature1"
base_feature "Base Feature1"
base_feature "Base Feature1"
base_feature "Base Feature1"
base_feature "Base Feature1"
base_feature "Base Feature1"
base_feature "Base Feature1"
base_feature "Base Feature1"
base_feature "Base Feature1"
base_feature "Base Feature1"
base_feature "Base Feature1"
base_feature "Base Feature1"
base_feature "Base Feature1"
base_feature "Base Feature1"
base_feature "Base Feature1"
base_feature "Base Feature1"
base_feature "Base Feature1"
base_feature "Base Feature1"
base_feature "Base Feature1"
base_feature "Base Feature1"
base_feature "Base Feature1"
base_feature "Base Feature1"
base_feature "Base Feature1"
base_feature "Base Feature1"
base_feature "Base Feature1"
base_feature "Base Feature1"
base_feature "Base Feature1"
base_feature "Base Feature1"
base_feature "Base Feature1"
base_feature "Base Feature1"
base_feature "Base Feature1"
base_feature "Base Feature1"
base_feature "Base Feature1"
base_feature "Base Feature1"
base_feature "Base Feature1"
base_feature "Base Feature1"
base_feature "Base Feature1"
base_feature "Base Feature1"
base_feature "Base Feature1"
base_feature "Base Feature1"
base_feature "Base Feature1"
base_feature "Base Feature1"
base_feature "Base Feature1"
base_feature "Base Feature1"
base_feature "Base Feature1"
base_feature "Base Feature1"
base_feature "Base Feature1"
base_feature "Base Feature1"
base_feature "Base Feature1"
base_feature "Base Feature1"
base_feature "Base Feature1"
base_feature "Base Feature1"
base_feature "Base Feature1"
base_feature "Base Feature1"
base_feature "Base Feature1"
base_feature "Base Feature1"
base_feature "Base Feature1"
base_feature "Base Feature1"
base_feature "Base Feature1"
base_feature "Base Feature1"
base_feature "Base Feature1"
base_feature "Base Feature1"
base_feature "Base Feature1"
base_feature "Base Feature1"
base_feature "Base Feature1"
base_feature "Base Feature1"
base_feature "Base Feature1"
base_feature "Base Feature1"
base_feature "Base Feature1"
base_feature "Base Feature1"
base_feature "Base Feature1"
base_feature "Base Feature1"
base_feature "Base Feature1"
base_feature "Base Feature1"
base_feature "Base Feature1"
base_feature "Base Feature1"
base_feature "Base Feature1"
base_feature "Base Feature1"
base_feature "Base Feature1"
base_feature "Base Feature1"
base_feature "Base Feature1"
base_feature "Base Feature1"
base_feature "Base Feature1"
base_feature "Base Feature1"
base_feature "Base Feature1"
base_feature "Base Feature1"
base_feature "Base Feature1"
base_feature "Base Feature1"
base_feature "Base Feature1"
base_feature "Base Feature1"
base_feature "Base Feature1"
base_feature "Base Feature1"
base_feature "Base Feature1"
base_feature "Base Feature1"
base_feature "Base Feature1"
base_feature "Base Feature1"
base_feature "Base Feature1"
base_feature "Base Feature1"
base_feature "Base Feature1"
base_feature "Base Feature1"
base_feature "Base Feature1"
base_feature "Base Feature1"
base_feature "Base Feature1"
base_feature "Base Feature1"
base_feature "Base Feature1"
base_feature "Base Feature1"
base_feature "Base Feature1"
base_feature "Base Feature1"
base_feature "Base Feature1"
base_feature "Base Feature1"
base_feature "Base Feature1"
base_feature "Base Feature1"
base_feature "Base Feature1"
base_feature "Base Feature1"
base_feature "Base Feature1"
base_feature "Base Feature1"
base_feature "Base Feature1"
base_feature "Base Feature1"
